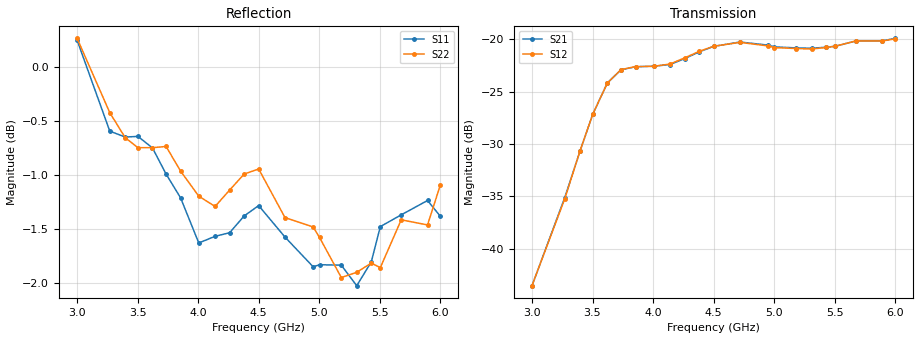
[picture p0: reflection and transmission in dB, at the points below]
!  26/11/2025  14:35:18
! Ref Plane: 0.000 mm
# MHZ S MA R  50
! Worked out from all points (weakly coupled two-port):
!   401 points, 3 GHz to 6 GHz, reference 50 ohm
!   highest |S21| = -19.91 dB at 6 GHz (marker M1); lowest = -43.5 dB at 3 GHz (marker M2)
!   lowest |S11| = -2.0 dB at 5.31 GHz (marker M3), VSWR 8.62, Z = 5.81 + j1.78 ohm
!   |S11| at or under -10 dB: nowhere
!   |S22| runs from -2.0 to 0.3 dB; largest |S21 - S12| = 0.0042
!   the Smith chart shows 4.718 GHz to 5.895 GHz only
!   S11 on the Smith chart (normalised r, x): 4.718 GHz: 6.66, -5.38; 4.95 GHz: 0.25, -1.16; 5.183 GHz: 0.11, -0.26; 5.43 GHz: 0.12, +0.36; 5.678 GHz: 0.23, +1.38; 5.895 GHz: 8, +7
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3000  1.029 -138.9  0.006652 50.9  0.006659 52.9  1.031 -105.0
3270  0.9339 151.4  0.01751 -17.1  0.01727 -14.5  0.9525 -171.1
3397.5  0.9281 108.1  0.02933 -57.6  0.02942 -56.3  0.9274 149.9
3502.5  0.9287 65.3  0.04392 -98.3  0.04397 -97.0  0.9176 112.0
3622.5  0.9174 14.2  0.06186 -150.7  0.06182 -149.3  0.9176 60.4
3735  0.8922 -35.0  0.07147 159.2  0.07164 160.8  0.9188 10.9
3855  0.8698 -83.1  0.07391 110.5  0.07405 112.1  0.895 -38.2
4005  0.829 -137.1  0.07437 57.8  0.07423 59.1  0.8714 -90.6
4140  0.8349 176.0  0.07571 14.8  0.0762 16.8  0.8619 -131.3
4260  0.8381 139.5  0.08079 -21.7  0.08142 -19.6  0.8771 -168.5
4380  0.8532 101.7  0.08699 -58.5  0.08752 -56.8  0.8922 155.6
4500  0.8627 62.8  0.09244 -97.4  0.09259 -95.8  0.897 118.0
4717.5  0.8342 -8.5  0.09704 -168.3  0.09664 -167.1  0.8517 51.3
4950  0.8082 -80.0  0.09377 121.9  0.09294 123.3  0.8433 -16.0
5002.5  0.81 -97.4  0.09197 106.2  0.09123 107.5  0.8339 -31.4
5182.5  0.8096 -150.7  0.09093 54.6  0.09033 55.7  0.799 -82.2
5310  0.7921 175.9  0.09057 19.2  0.08984 20.7  0.8035 -122.2
5430  0.8124 139.7  0.09166 -13.2  0.09137 -11.1  0.8114 -152.6
5505  0.8436 119.1  0.09257 -33.1  0.09264 -30.9  0.8075 -175.3
5677.5  0.8542 70.9  0.0982 -81.2  0.0983 -78.8  0.8497 138.5
5895  0.8674 6.9  0.09832 -144.2  0.09816 -142.0  0.8451 77.3
6000  0.853 -21.1  0.101 -172.3  0.1005 -170.6  0.8816 52.9
